VERSION 5.8 ;
UNITS DATABASE MICRONS 1000 ;

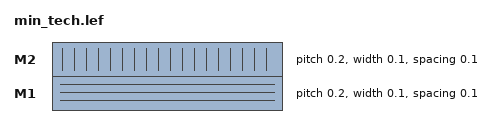
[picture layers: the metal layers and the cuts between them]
LAYER M1
  TYPE ROUTING ;
  DIRECTION HORIZONTAL ;
  PITCH 0.20 ;
  WIDTH 0.10 ;
  SPACING 0.10 ;
END M1

LAYER M2
  TYPE ROUTING ;
  DIRECTION VERTICAL ;
  PITCH 0.20 ;
  WIDTH 0.10 ;
  SPACING 0.10 ;
END M2

TRACKS X 0.05 DO 10 STEP 0.20 LAYER M1 ;
TRACKS Y 0.05 DO 10 STEP 0.20 LAYER M2 ;
